VERSION 5.8 ;
BUSBITCHARS "[]" ;
DIVIDERCHAR "/" ;
UNITS
    DATABASE MICRONS 1000 ;
END UNITS

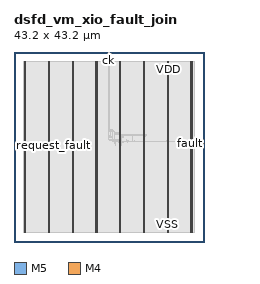
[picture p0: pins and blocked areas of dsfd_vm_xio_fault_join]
MACRO dsfd_vm_xio_fault_join
  FOREIGN dsfd_vm_xio_fault_join 0 0 ;
  CLASS BLOCK ;
  SIZE 43.2 BY 43.2 ;
  PIN ck
    DIRECTION INPUT ;
    USE SIGNAL ;
    PORT
      LAYER M5 ;
        RECT  21.552 43.116 21.576 43.2 ;
    END
  END ck
  PIN fault
    DIRECTION OUTPUT ;
    USE SIGNAL ;
    PORT
      LAYER M4 ;
        RECT  43.116 22.32 43.2 22.344 ;
    END
  END fault
  PIN request_fault
    DIRECTION INPUT ;
    USE SIGNAL ;
    PORT
      LAYER M4 ;
        RECT  0 21.84 0.084 21.864 ;
    END
  END request_fault
  PIN return_fault
    DIRECTION INPUT ;
    USE SIGNAL ;
    PORT
      LAYER M4 ;
        RECT  0 21.936 0.084 21.96 ;
    END
  END return_fault
  PIN rst_n
    DIRECTION INPUT ;
    USE SIGNAL ;
    PORT
      LAYER M5 ;
        RECT  21.648 43.116 21.672 43.2 ;
    END
  END rst_n
  PIN serial_level
    DIRECTION INPUT ;
    USE SIGNAL ;
    PORT
      LAYER M4 ;
        RECT  0 22.032 0.084 22.056 ;
    END
  END serial_level
  PIN serial_valid
    DIRECTION INPUT ;
    USE SIGNAL ;
    PORT
      LAYER M4 ;
        RECT  0 22.128 0.084 22.152 ;
    END
  END serial_valid
  PIN transport_fault
    DIRECTION INPUT ;
    USE SIGNAL ;
    PORT
      LAYER M4 ;
        RECT  0 22.224 0.084 22.248 ;
    END
  END transport_fault
  PIN VDD
    DIRECTION INOUT ;
    USE POWER ;
    PORT
      LAYER M5 ;
        RECT  40.392 2.151 40.512 41.049 ;
        RECT  34.992 2.151 35.112 41.049 ;
        RECT  29.592 2.151 29.712 41.049 ;
        RECT  24.192 2.151 24.312 41.049 ;
        RECT  18.792 2.151 18.912 41.049 ;
        RECT  13.392 2.151 13.512 41.049 ;
        RECT  7.992 2.151 8.112 41.049 ;
        RECT  2.592 2.151 2.712 41.049 ;
    END
  END VDD
  PIN VSS
    DIRECTION INOUT ;
    USE GROUND ;
    PORT
      LAYER M5 ;
        RECT  40.2 2.137 40.32 41.063 ;
        RECT  34.8 2.137 34.92 41.063 ;
        RECT  29.4 2.137 29.52 41.063 ;
        RECT  24 2.137 24.12 41.063 ;
        RECT  18.6 2.137 18.72 41.063 ;
        RECT  13.2 2.137 13.32 41.063 ;
        RECT  7.8 2.137 7.92 41.063 ;
        RECT  2.4 2.137 2.52 41.063 ;
    END
  END VSS
  OBS
    LAYER RVTN ;
     RECT  2.16 2.16 41.04 2.295 ;
     RECT  2.16 2.565 41.04 2.835 ;
     RECT  2.16 3.105 41.04 3.375 ;
     RECT  2.16 3.645 41.04 3.915 ;
     RECT  2.16 4.185 41.04 4.455 ;
     RECT  2.16 4.725 41.04 4.995 ;
     RECT  2.16 5.265 41.04 5.535 ;
     RECT  2.16 5.805 41.04 6.075 ;
     RECT  2.16 6.345 41.04 6.615 ;
     RECT  2.16 6.885 41.04 7.155 ;
     RECT  2.16 7.425 41.04 7.695 ;
     RECT  2.16 7.965 41.04 8.235 ;
     RECT  2.16 8.505 41.04 8.775 ;
     RECT  2.16 9.045 41.04 9.315 ;
     RECT  2.16 9.585 41.04 9.855 ;
     RECT  2.16 10.125 41.04 10.395 ;
     RECT  2.16 10.665 41.04 10.935 ;
     RECT  2.16 11.205 41.04 11.475 ;
     RECT  2.16 11.745 41.04 12.015 ;
     RECT  2.16 12.285 41.04 12.555 ;
     RECT  2.16 12.825 41.04 13.095 ;
     RECT  2.16 13.365 41.04 13.635 ;
     RECT  2.16 13.905 41.04 14.175 ;
     RECT  2.16 14.445 41.04 14.715 ;
     RECT  2.16 14.985 41.04 15.255 ;
     RECT  2.16 15.525 41.04 15.795 ;
     RECT  2.16 16.065 41.04 16.335 ;
     RECT  2.16 16.605 41.04 16.875 ;
     RECT  2.16 17.145 41.04 17.415 ;
     RECT  2.16 17.685 41.04 17.955 ;
     RECT  2.16 18.225 41.04 18.495 ;
     RECT  2.16 18.765 41.04 19.035 ;
     RECT  2.16 19.305 41.04 19.575 ;
     RECT  2.16 19.845 41.04 20.115 ;
     RECT  2.16 20.385 41.04 20.655 ;
     RECT  2.16 20.925 41.04 21.195 ;
     RECT  2.16 21.465 41.04 21.735 ;
     RECT  2.16 22.005 41.04 22.275 ;
     RECT  2.16 22.545 41.04 22.815 ;
     RECT  2.16 23.085 41.04 23.355 ;
     RECT  2.16 23.625 41.04 23.895 ;
     RECT  2.16 24.165 41.04 24.435 ;
     RECT  2.16 24.705 41.04 24.975 ;
     RECT  2.16 25.245 41.04 25.515 ;
     RECT  2.16 25.785 41.04 26.055 ;
     RECT  2.16 26.325 41.04 26.595 ;
     RECT  2.16 26.865 41.04 27.135 ;
     RECT  2.16 27.405 41.04 27.675 ;
     RECT  2.16 27.945 41.04 28.215 ;
     RECT  2.16 28.485 41.04 28.755 ;
     RECT  2.16 29.025 41.04 29.295 ;
     RECT  2.16 29.565 41.04 29.835 ;
     RECT  2.16 30.105 41.04 30.375 ;
     RECT  2.16 30.645 41.04 30.915 ;
     RECT  2.16 31.185 41.04 31.455 ;
     RECT  2.16 31.725 41.04 31.995 ;
     RECT  2.16 32.265 41.04 32.535 ;
     RECT  2.16 32.805 41.04 33.075 ;
     RECT  2.16 33.345 41.04 33.615 ;
     RECT  2.16 33.885 41.04 34.155 ;
     RECT  2.16 34.425 41.04 34.695 ;
     RECT  2.16 34.965 41.04 35.235 ;
     RECT  2.16 35.505 41.04 35.775 ;
     RECT  2.16 36.045 41.04 36.315 ;
     RECT  2.16 36.585 41.04 36.855 ;
     RECT  2.16 37.125 41.04 37.395 ;
     RECT  2.16 37.665 41.04 37.935 ;
     RECT  2.16 38.205 41.04 38.475 ;
     RECT  2.16 38.745 41.04 39.015 ;
     RECT  2.16 39.285 41.04 39.555 ;
     RECT  2.16 39.825 41.04 40.095 ;
     RECT  2.16 40.365 41.04 40.635 ;
     RECT  2.16 40.905 41.04 41.04 ;
    LAYER RVTP ;
     RECT  2.16 2.295 41.04 2.565 ;
     RECT  2.16 2.835 41.04 3.105 ;
     RECT  2.16 3.375 41.04 3.645 ;
     RECT  2.16 3.915 41.04 4.185 ;
     RECT  2.16 4.455 41.04 4.725 ;
     RECT  2.16 4.995 41.04 5.265 ;
     RECT  2.16 5.535 41.04 5.805 ;
     RECT  2.16 6.075 41.04 6.345 ;
     RECT  2.16 6.615 41.04 6.885 ;
     RECT  2.16 7.155 41.04 7.425 ;
     RECT  2.16 7.695 41.04 7.965 ;
     RECT  2.16 8.235 41.04 8.505 ;
     RECT  2.16 8.775 41.04 9.045 ;
     RECT  2.16 9.315 41.04 9.585 ;
     RECT  2.16 9.855 41.04 10.125 ;
     RECT  2.16 10.395 41.04 10.665 ;
     RECT  2.16 10.935 41.04 11.205 ;
     RECT  2.16 11.475 41.04 11.745 ;
     RECT  2.16 12.015 41.04 12.285 ;
     RECT  2.16 12.555 41.04 12.825 ;
     RECT  2.16 13.095 41.04 13.365 ;
     RECT  2.16 13.635 41.04 13.905 ;
     RECT  2.16 14.175 41.04 14.445 ;
     RECT  2.16 14.715 41.04 14.985 ;
     RECT  2.16 15.255 41.04 15.525 ;
     RECT  2.16 15.795 41.04 16.065 ;
     RECT  2.16 16.335 41.04 16.605 ;
     RECT  2.16 16.875 41.04 17.145 ;
     RECT  2.16 17.415 41.04 17.685 ;
     RECT  2.16 17.955 41.04 18.225 ;
     RECT  2.16 18.495 41.04 18.765 ;
     RECT  2.16 19.035 41.04 19.305 ;
     RECT  2.16 19.575 41.04 19.845 ;
     RECT  2.16 20.115 41.04 20.385 ;
     RECT  2.16 20.655 41.04 20.925 ;
     RECT  2.16 21.195 41.04 21.465 ;
     RECT  2.16 21.735 41.04 22.005 ;
     RECT  2.16 22.275 41.04 22.545 ;
     RECT  2.16 22.815 41.04 23.085 ;
     RECT  2.16 23.355 41.04 23.625 ;
     RECT  2.16 23.895 41.04 24.165 ;
     RECT  2.16 24.435 41.04 24.705 ;
     RECT  2.16 24.975 41.04 25.245 ;
     RECT  2.16 25.515 41.04 25.785 ;
     RECT  2.16 26.055 41.04 26.325 ;
     RECT  2.16 26.595 41.04 26.865 ;
     RECT  2.16 27.135 41.04 27.405 ;
     RECT  2.16 27.675 41.04 27.945 ;
     RECT  2.16 28.215 41.04 28.485 ;
     RECT  2.16 28.755 41.04 29.025 ;
     RECT  2.16 29.295 41.04 29.565 ;
     RECT  2.16 29.835 41.04 30.105 ;
     RECT  2.16 30.375 41.04 30.645 ;
     RECT  2.16 30.915 41.04 31.185 ;
     RECT  2.16 31.455 41.04 31.725 ;
     RECT  2.16 31.995 41.04 32.265 ;
     RECT  2.16 32.535 41.04 32.805 ;
     RECT  2.16 33.075 41.04 33.345 ;
     RECT  2.16 33.615 41.04 33.885 ;
     RECT  2.16 34.155 41.04 34.425 ;
     RECT  2.16 34.695 41.04 34.965 ;
     RECT  2.16 35.235 41.04 35.505 ;
     RECT  2.16 35.775 41.04 36.045 ;
     RECT  2.16 36.315 41.04 36.585 ;
     RECT  2.16 36.855 41.04 37.125 ;
     RECT  2.16 37.395 41.04 37.665 ;
     RECT  2.16 37.935 41.04 38.205 ;
     RECT  2.16 38.475 41.04 38.745 ;
     RECT  2.16 39.015 41.04 39.285 ;
     RECT  2.16 39.555 41.04 39.825 ;
     RECT  2.16 40.095 41.04 40.365 ;
     RECT  2.16 40.635 41.04 40.905 ;
    LAYER M1 ;
     RECT  2.16 2.151 41.04 41.049 ;
    LAYER M2 ;
     RECT  0.103 22.05 2.16 22.068 ;
     RECT  2.16 2.151 41.04 41.049 ;
     RECT  41.04 22.212 43.115 22.23 ;
    LAYER M3 ;
     RECT  2.415 2.143 2.505 2.413 ;
     RECT  7.815 2.143 7.905 2.413 ;
     RECT  13.215 2.143 13.305 2.413 ;
     RECT  18.615 2.143 18.705 2.413 ;
     RECT  24.015 2.143 24.105 2.413 ;
     RECT  29.415 2.143 29.505 2.413 ;
     RECT  34.815 2.143 34.905 2.413 ;
     RECT  40.215 2.143 40.305 2.413 ;
     RECT  2.415 2.413 2.697 21.739 ;
     RECT  2.304 21.739 2.697 21.811 ;
     RECT  24.015 2.413 24.297 21.901 ;
     RECT  2.304 21.811 2.862 21.937 ;
     RECT  2.304 21.937 2.934 22.123 ;
     RECT  40.215 2.413 40.497 22.171 ;
     RECT  0.108 22.045 0.126 22.253 ;
     RECT  40.215 22.171 40.698 22.271 ;
     RECT  2.268 22.123 2.934 22.315 ;
     RECT  22.968 21.937 22.986 22.315 ;
     RECT  43.092 22.207 43.11 22.349 ;
     RECT  2.268 22.315 3.15 22.469 ;
     RECT  40.215 22.271 40.59 22.469 ;
     RECT  2.268 22.469 2.697 22.505 ;
     RECT  22.932 22.315 22.986 22.585 ;
     RECT  24.015 21.901 24.534 22.585 ;
     RECT  22.86 22.585 22.986 22.621 ;
     RECT  23.76 22.585 24.534 22.621 ;
     RECT  40.215 22.469 40.497 22.621 ;
     RECT  22.86 22.621 23.022 22.711 ;
     RECT  23.76 22.621 24.786 22.739 ;
     RECT  38.592 22.621 38.61 22.747 ;
     RECT  23.76 22.739 24.606 22.811 ;
     RECT  38.412 22.747 38.61 22.811 ;
     RECT  22.824 22.711 23.022 22.819 ;
     RECT  23.76 22.811 24.498 22.819 ;
     RECT  25.884 22.585 25.902 22.819 ;
     RECT  22.824 22.819 24.498 22.855 ;
     RECT  25.632 22.819 25.902 22.855 ;
     RECT  25.56 22.855 25.902 22.891 ;
     RECT  34.815 2.413 35.097 22.891 ;
     RECT  39.132 22.855 39.15 22.891 ;
     RECT  39.924 22.621 40.497 22.891 ;
     RECT  25.56 22.891 26.046 23.009 ;
     RECT  27.36 22.747 27.378 23.009 ;
     RECT  34.776 22.891 35.097 23.009 ;
     RECT  39.132 22.891 40.497 23.009 ;
     RECT  39.708 23.009 40.497 23.045 ;
     RECT  22.392 22.855 24.498 23.161 ;
     RECT  26.928 23.125 26.946 23.165 ;
     RECT  25.56 23.009 25.65 23.351 ;
     RECT  21.672 23.161 24.498 23.395 ;
     RECT  21.528 23.395 24.498 23.701 ;
     RECT  21.528 23.701 24.966 23.891 ;
     RECT  21.528 23.891 24.462 23.927 ;
     RECT  21.996 23.927 24.462 23.933 ;
     RECT  29.415 2.413 29.697 24.061 ;
     RECT  22.356 23.933 24.462 24.089 ;
     RECT  25.992 24.205 26.01 24.241 ;
     RECT  29.415 24.061 29.97 24.241 ;
     RECT  25.992 24.241 26.226 24.413 ;
     RECT  29.415 24.241 30.222 24.413 ;
     RECT  26.208 24.413 26.226 24.509 ;
     RECT  22.356 24.089 24.297 24.745 ;
     RECT  22.176 24.745 24.297 24.971 ;
     RECT  22.176 24.971 22.878 25.051 ;
     RECT  21.564 25.051 22.878 25.099 ;
     RECT  21.42 25.099 22.878 25.169 ;
     RECT  21.42 25.169 22.734 25.439 ;
     RECT  21.42 25.439 22.374 25.547 ;
     RECT  21.42 25.547 22.194 25.583 ;
     RECT  21.672 25.583 21.69 34.456 ;
     RECT  21.672 34.456 21.726 34.457 ;
     RECT  21.708 34.457 21.726 38.947 ;
     RECT  21.672 38.947 21.726 39.047 ;
     RECT  2.415 22.505 2.697 40.787 ;
     RECT  7.815 2.413 8.097 40.787 ;
     RECT  13.215 2.413 13.497 40.787 ;
     RECT  18.615 2.413 18.897 40.787 ;
     RECT  24.015 24.971 24.297 40.787 ;
     RECT  29.415 24.413 29.697 40.787 ;
     RECT  34.815 23.009 35.097 40.787 ;
     RECT  40.215 23.045 40.497 40.787 ;
     RECT  21.672 39.047 21.69 41.021 ;
     RECT  2.415 40.787 2.505 41.057 ;
     RECT  7.815 40.787 7.905 41.057 ;
     RECT  13.215 40.787 13.305 41.057 ;
     RECT  18.615 40.787 18.705 41.057 ;
     RECT  24.015 40.787 24.105 41.057 ;
     RECT  29.415 40.787 29.505 41.057 ;
     RECT  34.815 40.787 34.905 41.057 ;
     RECT  40.215 40.787 40.305 41.057 ;
    LAYER M4 ;
     RECT  0.06 21.84 0.137 22.248 ;
     RECT  0.137 21.84 2.408 22.152 ;
     RECT  2.408 2.148 2.512 41.052 ;
     RECT  2.512 2.418 2.704 40.782 ;
     RECT  7.808 2.148 7.912 41.052 ;
     RECT  7.912 2.418 8.104 40.782 ;
     RECT  13.208 2.148 13.312 41.052 ;
     RECT  13.312 2.418 13.504 40.782 ;
     RECT  18.608 2.148 18.712 41.052 ;
     RECT  18.712 2.418 18.904 40.782 ;
     RECT  21.409 25.104 21.541 25.128 ;
     RECT  21.617 40.992 21.701 41.016 ;
     RECT  21.541 24.144 21.973 25.128 ;
     RECT  21.973 23.904 22.381 25.128 ;
     RECT  22.381 23.328 22.853 25.128 ;
     RECT  22.853 23.328 23.893 24.504 ;
     RECT  23.893 22.752 24.008 24.504 ;
     RECT  24.008 2.148 24.112 41.052 ;
     RECT  24.112 2.418 24.304 40.782 ;
     RECT  24.304 24.144 26.237 24.504 ;
     RECT  24.304 22.752 26.876 22.776 ;
     RECT  26.876 22.752 26.963 23.16 ;
     RECT  26.963 22.752 29.408 22.776 ;
     RECT  26.237 24.144 29.408 24.408 ;
     RECT  29.408 2.148 29.512 41.052 ;
     RECT  29.512 2.418 29.704 40.782 ;
     RECT  29.704 24.144 29.981 24.408 ;
     RECT  29.981 24.384 30.233 24.408 ;
     RECT  29.704 22.752 34.808 22.776 ;
     RECT  34.808 2.148 34.912 41.052 ;
     RECT  34.912 2.418 35.104 40.782 ;
     RECT  35.104 22.752 38.441 22.776 ;
     RECT  40.208 2.148 40.312 41.052 ;
     RECT  40.312 2.418 40.504 40.782 ;
     RECT  43.081 22.32 43.164 22.344 ;
    LAYER M5 ;
     RECT  2.4 2.137 2.52 2.151 ;
     RECT  7.8 2.137 7.92 2.151 ;
     RECT  13.2 2.137 13.32 2.151 ;
     RECT  18.6 2.137 18.72 2.151 ;
     RECT  24 2.137 24.12 2.151 ;
     RECT  29.4 2.137 29.52 2.151 ;
     RECT  34.8 2.137 34.92 2.151 ;
     RECT  40.2 2.137 40.32 2.151 ;
     RECT  24 2.151 24.312 22.741 ;
     RECT  23.904 22.741 24.312 23.555 ;
     RECT  21.984 23.893 22.008 24.133 ;
     RECT  26.928 23.125 26.952 24.419 ;
     RECT  21.552 24.133 22.008 25.139 ;
     RECT  21.552 25.139 21.576 40.981 ;
     RECT  2.4 2.151 2.712 41.049 ;
     RECT  7.8 2.151 8.112 41.049 ;
     RECT  13.2 2.151 13.512 41.049 ;
     RECT  18.6 2.151 18.912 41.049 ;
     RECT  24 23.555 24.312 41.049 ;
     RECT  29.4 2.151 29.712 41.049 ;
     RECT  34.8 2.151 35.112 41.049 ;
     RECT  40.2 2.151 40.512 41.049 ;
     RECT  2.4 41.049 2.52 41.063 ;
     RECT  7.8 41.049 7.92 41.063 ;
     RECT  13.2 41.049 13.32 41.063 ;
     RECT  18.6 41.049 18.72 41.063 ;
     RECT  24 41.049 24.12 41.063 ;
     RECT  29.4 41.049 29.52 41.063 ;
     RECT  34.8 41.049 34.92 41.063 ;
     RECT  40.2 41.049 40.32 41.063 ;
     RECT  21.552 40.981 21.672 43.152 ;
  END
END dsfd_vm_xio_fault_join
END LIBRARY
